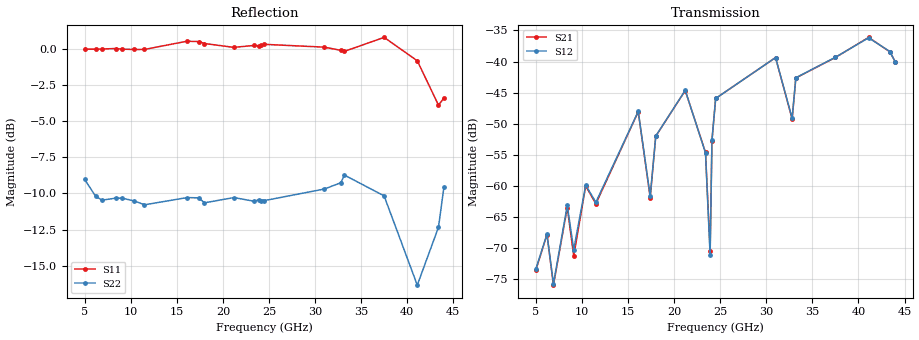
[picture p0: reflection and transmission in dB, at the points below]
!MADT-011000 Measured on a PCB but de-embedded
!Data should be considered typical for reference purposes
!IMPORTANT >>>>  Port 2 is the device.  Port 1 is meaningless in this data.
!DC Conditions (User defined)
!Stage1	Vd1		4.5000		Id1_offset (mA)	-0.059080	Vg1		0.0000		Ig1_offset (mA)	0.000000
!RF off	!DC Conditions
!Stage 1	Vd = 4.51	Id = 	0.159	Vg = 0.000	Ig = 0.000000000
!User :
!Version : 2380
!Flatness		Pin-(dBm)	50.00
!freq-unit	param-type	data-format	keyword	impedance-ohms
#	GHZ	S	RI	R	50.000000
!Freq	ReS11	ImS11	ReS21	ImS21	ReS12	ImS12	ReS22	ImS22
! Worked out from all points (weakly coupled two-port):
!   391 points, 5 GHz to 44 GHz, reference 50 ohm
!   highest |S21| = -36.13 dB at 41.1 GHz (marker M1); lowest = -75.9 dB at 6.9 GHz (marker M2)
!   lowest |S11| = -3.9 dB at 43.4 GHz (marker M3), VSWR 4.57, Z = 12.8 - j20.2 ohm
!   |S11| at or under -10 dB: nowhere
!   |S22| runs from -17.4 to -8.7 dB; largest |S21 - S12| = 0.00036
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5  0.9734 -0.2384  2.2e-05 0.000211  3.1e-05 0.000215  0.3458 0.0756
6.2  0.9563 -0.2995  7.3e-05 0.000401  8.5e-05 0.000401  0.2928 -0.0992
6.9  0.9463 -0.3346  7.9e-05 0.000139  8.7e-05 0.000139  0.2454 -0.1723
8.4  0.9073 -0.4382  0.000634 -0.000219  0.000656 -0.000241  0.1217 -0.2794
9.1  0.8824 -0.475  0.000127 -0.000243  0.000148 -0.000271  0.0655 -0.2973
10.4  0.8408 -0.5412  0.000193 -0.000983  0.000184 -0.001  -0.0317 -0.2963
11.5  0.8111 -0.5849  0.000218 -0.000686  0.000203 -0.000712  -0.1085 -0.2677
16.1  0.7669 -0.7432  -0.00164 -0.00359  -0.00167 -0.00361  -0.3059 -0.00718
17.4  0.7148 -0.7897  -0.000121 -0.000799  -0.000145 -0.000815  -0.2967 0.0728
18  0.6809 -0.7975  0.00174 -0.00181  0.00171 -0.00185  -0.2701 0.1148
21.2  0.4716 -0.9008  -0.00486 -0.00326  -0.0049 -0.00323  -0.0878 0.2932
23.4  0.3251 -0.9802  -0.00127 -0.00136  -0.00128 -0.00133  0.0325 0.2955
23.9  0.2981 -0.9864  5.8e-05 -0.000295  6.7e-05 -0.000269  0.0628 0.2942
24.1  0.2872 -0.9942  0.00231 -0.000194  0.00233 -0.000191  0.0712 0.2901
24.5  0.2667 -1.007  0.00241 -0.00444  0.00237 -0.00446  0.0912 0.2845
31  -0.0733 -1.016  -0.00118 -0.0107  -0.00114 -0.0107  0.303 -0.1246
32.8  -0.1577 -0.9805  0.000188 -0.00345  0.000122 -0.0035  0.2633 -0.2221
33.2  -0.1729 -0.9697  0.00023 -0.00738  0.000116 -0.00741  0.2536 -0.2643
37.5  -0.5342 -0.963  0.00621 -0.00882  0.00626 -0.00884  -0.0371 -0.308
41.1  -0.6593 -0.6323  -0.00272 -0.0154  -0.00257 -0.0153  -0.149 -0.0302
43.4  -0.4418 -0.464  -0.00982 -0.00684  -0.00987 -0.0069  0.0712 0.2307
44  -0.4315 -0.524  -0.00982 -0.00153  -0.00975 -0.00159  0.2226 0.2494
